VERSION 5.8 ;
BUSBITCHARS "[]" ;
DIVIDERCHAR "/" ;

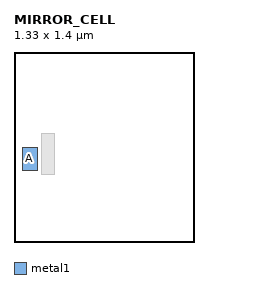
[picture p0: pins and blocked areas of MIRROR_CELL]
MACRO MIRROR_CELL
  CLASS CORE ;
  SIZE 1.33 BY 1.4 ;
  SYMMETRY X Y ;
  SITE FreePDK45_38x28_10R_NP_162NW_34O ;
  PIN A
    DIRECTION INPUT ;
    USE SIGNAL ;
    PORT
      LAYER metal1 ;
        RECT 0.06 0.525 0.17 0.7 ;
    END
  END A
  OBS
    LAYER metal1 ;
      # Keep the OBS physically separate from the signal pin.  Its mirrored
      # position still overlaps the supply via in the DEF fixture.
      RECT 0.2 0.5 0.3 0.8 ;
  END
END MIRROR_CELL

END LIBRARY
